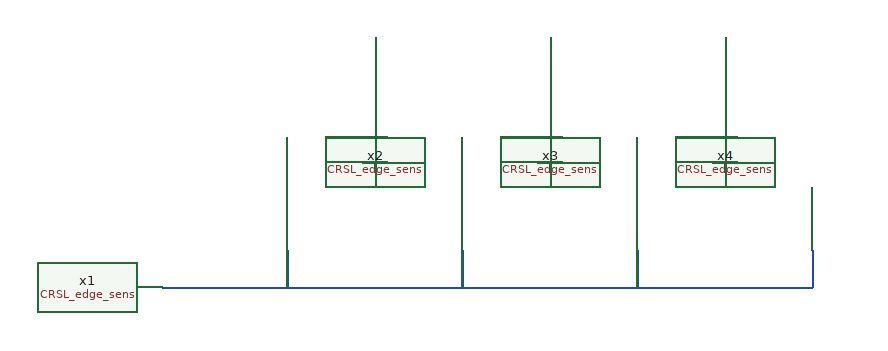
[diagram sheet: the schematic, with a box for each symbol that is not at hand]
v {xschem version=3.4.3 file_version=1.2
}
G {}
K {}
V {}
S {}
E {}
N 20 -20 540 -20 {
lab=#net1}
N 540 -50 540 -20 {
lab=#net1}
N 400 -50 400 -20 {
lab=#net1}
N 260 -50 260 -20 {
lab=#net1}
N 120 -50 120 -20 {
lab=#net1}
N 180 -120 200 -120 {
lab=#net2}
N 460 -120 480 -120 {
lab=#net3}
N 320 -120 340 -120 {
lab=#net4}
N 180 -140 200 -140 {
lab=#net5}
N 320 -140 340 -140 {
lab=#net6}
N 460 -140 480 -140 {
lab=#net7}
N 470 -220 470 -140 {
lab=#net7}
N 330 -220 330 -140 {}
N 190 -220 190 -140 {}
C {/home/madvlsi/Documents/algorithmic-ada-converter/schematics/CRSL_edge_sens.sym} 30 -40 0 0 {name=x1}
C {/home/madvlsi/Documents/algorithmic-ada-converter/schematics/CRSL_edge_sens.sym} 170 -40 0 0 {name=x2}
C {/home/madvlsi/Documents/algorithmic-ada-converter/schematics/CRSL_edge_sens.sym} 310 -40 0 0 {name=x3}
C {/home/madvlsi/Documents/algorithmic-ada-converter/schematics/CRSL_edge_sens.sym} 450 -40 0 0 {name=x4}
